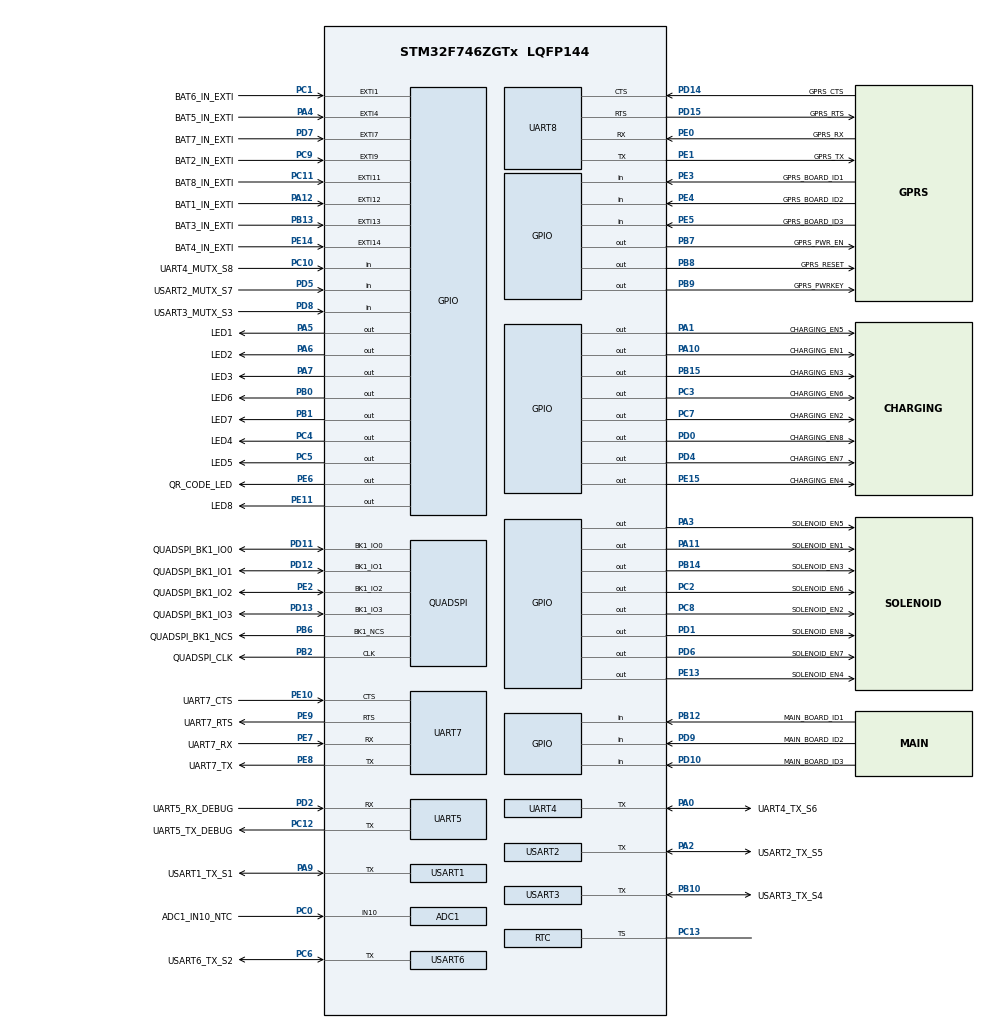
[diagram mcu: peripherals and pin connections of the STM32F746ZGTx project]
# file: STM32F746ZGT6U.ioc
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ADC1.Channel-1\#ChannelRegularConversion=ADC_CHANNEL_10
ADC1.Channel-2\#ChannelRegularConversion=ADC_CHANNEL_TEMPSENSOR
ADC1.ClockPrescaler=ADC_CLOCK_SYNC_PCLK_DIV8
ADC1.DiscontinuousConvMode=ENABLE
ADC1.NbrOfConversion=2
ADC1.NbrOfConversionFlag=1
ADC1.NbrOfDiscConversion=2
ADC1.Rank-1\#ChannelRegularConversion=1
ADC1.Rank-2\#ChannelRegularConversion=2
ADC1.SamplingTime-1\#ChannelRegularConversion=ADC_SAMPLETIME_480CYCLES
ADC1.SamplingTime-2\#ChannelRegularConversion=ADC_SAMPLETIME_480CYCLES
ADC1.ScanConvMode=ENABLE
ADC1.master=1
FREERTOS.Tasks01=defaultTask,0,128,StartDefaultTask,Default,NULL
Mcu.Family=STM32F7
Mcu.Name=STM32F746ZGTx
Mcu.Package=LQFP144
NVIC.EXTI15_10_IRQn=true\:5\:0\:false\:true\:true\:8\:true\:true\:true
NVIC.EXTI1_IRQn=true\:5\:0\:false\:true\:true\:2\:true\:true\:true
NVIC.EXTI4_IRQn=true\:5\:0\:false\:true\:true\:3\:true\:true\:true
NVIC.EXTI9_5_IRQn=true\:5\:0\:false\:true\:true\:4\:true\:true\:true
NVIC.PriorityGroup=NVIC_PRIORITYGROUP_4
NVIC.TIM6_DAC_IRQn=true\:5\:0\:false\:true\:true\:11\:true\:true\:true
NVIC.UART4_IRQn=true\:5\:0\:false\:true\:true\:9\:true\:true\:true
NVIC.UART5_IRQn=true\:5\:0\:false\:true\:true\:10\:true\:true\:true
NVIC.UART7_IRQn=true\:5\:0\:false\:true\:true\:13\:true\:true\:true
NVIC.UART8_IRQn=true\:5\:0\:false\:true\:true\:14\:true\:true\:true
NVIC.USART1_IRQn=true\:5\:0\:false\:true\:true\:5\:true\:true\:true
NVIC.USART2_IRQn=true\:5\:0\:false\:true\:true\:6\:true\:true\:true
NVIC.USART3_IRQn=true\:5\:0\:false\:true\:true\:7\:true\:true\:true
NVIC.USART6_IRQn=true\:5\:0\:false\:true\:true\:12\:true\:true\:true
NVIC.WWDG_IRQn=true\:5\:0\:false\:true\:true\:1\:true\:true\:true
PA0/WKUP.GPIO_Label=UART4_TX_S6
PA0/WKUP.GPIO_Speed=GPIO_SPEED_FREQ_HIGH
PA0/WKUP.Mode=Half_duplex(single_wire_mode)
PA0/WKUP.Signal=UART4_TX
PA1.GPIO_Label=CHARGING_EN5
PA1.GPIO_PuPd=GPIO_PULLDOWN
PA1.Signal=GPIO_Output
PA10.GPIO_Label=CHARGING_EN1
PA10.GPIO_PuPd=GPIO_PULLDOWN
PA10.Signal=GPIO_Output
PA11.GPIO_Label=SOLENOID_EN1
PA11.GPIO_PuPd=GPIO_PULLDOWN
PA11.Signal=GPIO_Output
PA12.GPIO_Label=BAT1_IN_EXTI
PA12.GPIO_ModeDefaultEXTI=GPIO_MODE_IT_RISING_FALLING
PA12.Signal=GPXTI12
PA13.GPIO_Label=JTMS_SWDIO
PA13.Mode=JTAG_5_pins
PA13.Signal=SYS_JTMS-SWDIO
PA14.GPIO_Label=JTCK_SWCLK
PA14.Mode=JTAG_5_pins
PA14.Signal=SYS_JTCK-SWCLK
PA15.GPIO_Label=JTDI
PA15.Mode=JTAG_5_pins
PA15.Signal=SYS_JTDI
PA2.GPIO_Label=USART2_TX_S5
PA2.GPIO_Speed=GPIO_SPEED_FREQ_HIGH
PA2.Mode=Half_duplex(single_wire_mode)
PA2.Signal=USART2_TX
PA3.GPIO_Label=SOLENOID_EN5
PA3.GPIO_PuPd=GPIO_PULLDOWN
PA3.Signal=GPIO_Output
PA4.GPIO_Label=BAT5_IN_EXTI
PA4.GPIO_ModeDefaultEXTI=GPIO_MODE_IT_RISING_FALLING
PA4.Signal=GPXTI4
PA5.GPIO_Label=LED1
PA5.GPIO_PuPd=GPIO_PULLDOWN
PA5.Signal=GPIO_Output
PA6.GPIO_Label=LED2
PA6.GPIO_PuPd=GPIO_PULLDOWN
PA6.Signal=GPIO_Output
PA7.GPIO_Label=LED3
PA7.GPIO_PuPd=GPIO_PULLDOWN
PA7.Signal=GPIO_Output
PA9.GPIO_Label=USART1_TX_S1
PA9.GPIO_Speed=GPIO_SPEED_FREQ_HIGH
PA9.Mode=Half_duplex(single_wire_mode)
PA9.Signal=USART1_TX
PB0.GPIO_Label=LED6
PB0.GPIO_PuPd=GPIO_PULLDOWN
PB0.Signal=GPIO_Output
PB1.GPIO_Label=LED7
PB1.GPIO_PuPd=GPIO_PULLDOWN
PB1.Signal=GPIO_Output
PB10.GPIO_Label=USART3_TX_S4
PB10.GPIO_Speed=GPIO_SPEED_FREQ_HIGH
PB10.Mode=Half_duplex(single_wire_mode)
PB10.Signal=USART3_TX
PB12.GPIO_Label=MAIN_BOARD_ID1
PB12.Signal=GPIO_Input
PB13.GPIO_Label=BAT3_IN_EXTI
PB13.GPIO_ModeDefaultEXTI=GPIO_MODE_IT_RISING_FALLING
PB13.Signal=GPXTI13
PB14.GPIO_Label=SOLENOID_EN3
PB14.GPIO_PuPd=GPIO_PULLDOWN
PB14.Signal=GPIO_Output
PB15.GPIO_Label=CHARGING_EN3
PB15.GPIO_PuPd=GPIO_PULLDOWN
PB15.Signal=GPIO_Output
PB2.GPIO_Label=QUADSPI_CLK
PB2.Mode=Single Bank 1
PB2.Signal=QUADSPI_CLK
PB3.GPIO_Label=JTDO_SWO
PB3.Mode=JTAG_5_pins
PB3.Signal=SYS_JTDO-SWO
PB4.GPIO_Label=JTRST
PB4.Mode=JTAG_5_pins
PB4.Signal=SYS_JTRST
PB6.GPIO_Label=QUADSPI_BK1_NCS
PB6.Mode=Single Bank 1
PB6.Signal=QUADSPI_BK1_NCS
PB7.GPIO_Label=GPRS_PWR_EN
PB7.GPIO_PuPd=GPIO_PULLDOWN
PB7.Signal=GPIO_Output
PB8.GPIO_Label=GPRS_RESET
PB8.GPIO_PuPd=GPIO_PULLDOWN
PB8.Signal=GPIO_Output
PB9.GPIO_Label=GPRS_PWRKEY
PB9.GPIO_PuPd=GPIO_PULLDOWN
PB9.Signal=GPIO_Output
PC0.GPIO_Label=ADC1_IN10_NTC
PC0.Signal=ADCx_IN10
PC1.GPIO_Label=BAT6_IN_EXTI
PC1.GPIO_ModeDefaultEXTI=GPIO_MODE_IT_RISING_FALLING
PC1.Signal=GPXTI1
PC10.GPIO_Label=UART4_MUTX_S8
PC10.Signal=GPIO_Input
PC11.GPIO_Label=BAT8_IN_EXTI
PC11.GPIO_ModeDefaultEXTI=GPIO_MODE_IT_RISING_FALLING
PC11.Signal=GPXTI11
PC12.GPIO_Label=UART5_TX_DEBUG
PC12.GPIO_Speed=GPIO_SPEED_FREQ_HIGH
PC12.Mode=Asynchronous
PC12.Signal=UART5_TX
PC13.Mode=Timestamp enabled - Input Enabled to TS
PC13.Signal=RTC_TS
PC14/OSC32_IN.GPIO_Label=RCC_OSC32_IN
PC14/OSC32_IN.Mode=LSE-External-Oscillator
PC14/OSC32_IN.Signal=RCC_OSC32_IN
PC15/OSC32_OUT.GPIO_Label=RCC_OSC32_OUT
PC15/OSC32_OUT.Mode=LSE-External-Oscillator
PC15/OSC32_OUT.Signal=RCC_OSC32_OUT
PC2.GPIO_Label=SOLENOID_EN6
PC2.GPIO_PuPd=GPIO_PULLDOWN
PC2.Signal=GPIO_Output
PC3.GPIO_Label=CHARGING_EN6
PC3.GPIO_PuPd=GPIO_PULLDOWN
PC3.Signal=GPIO_Output
PC4.GPIO_Label=LED4
PC4.GPIO_PuPd=GPIO_PULLDOWN
PC4.Signal=GPIO_Output
PC5.GPIO_Label=LED5
PC5.GPIO_PuPd=GPIO_PULLDOWN
PC5.Signal=GPIO_Output
PC6.GPIO_Label=USART6_TX_S2
PC6.GPIO_Speed=GPIO_SPEED_FREQ_HIGH
PC6.Mode=Half_duplex(single_wire_mode)
PC6.Signal=USART6_TX
PC7.GPIO_Label=CHARGING_EN2
PC7.GPIO_PuPd=GPIO_PULLDOWN
PC7.Signal=GPIO_Output
PC8.GPIO_Label=SOLENOID_EN2
PC8.GPIO_PuPd=GPIO_PULLDOWN
PC8.Signal=GPIO_Output
PC9.GPIO_Label=BAT2_IN_EXTI
PC9.GPIO_ModeDefaultEXTI=GPIO_MODE_IT_RISING_FALLING
PC9.Signal=GPXTI9
PD0.GPIO_Label=CHARGING_EN8
PD0.GPIO_PuPd=GPIO_PULLDOWN
PD0.Signal=GPIO_Output
PD1.GPIO_Label=SOLENOID_EN8
PD1.GPIO_PuPd=GPIO_PULLDOWN
PD1.Signal=GPIO_Output
PD10.GPIO_Label=MAIN_BOARD_ID3
PD10.Signal=GPIO_Input
PD11.GPIO_Label=QUADSPI_BK1_IO0
PD11.Mode=Single Bank 1
PD11.Signal=QUADSPI_BK1_IO0
PD12.GPIO_Label=QUADSPI_BK1_IO1
PD12.Mode=Single Bank 1
PD12.Signal=QUADSPI_BK1_IO1
PD13.GPIO_Label=QUADSPI_BK1_IO3
PD13.Mode=Single Bank 1
PD13.Signal=QUADSPI_BK1_IO3
PD14.GPIO_Label=GPRS_CTS
PD14.GPIO_Speed=GPIO_SPEED_FREQ_MEDIUM
PD14.Mode=CTS_RTS
PD14.Signal=UART8_CTS
PD15.GPIO_Label=GPRS_RTS
PD15.GPIO_Speed=GPIO_SPEED_FREQ_MEDIUM
PD15.Mode=CTS_RTS
PD15.Signal=UART8_RTS
PD2.GPIO_Label=UART5_RX_DEBUG
PD2.GPIO_Speed=GPIO_SPEED_FREQ_HIGH
PD2.Mode=Asynchronous
PD2.Signal=UART5_RX
PD4.GPIO_Label=CHARGING_EN7
PD4.GPIO_PuPd=GPIO_PULLDOWN
PD4.Signal=GPIO_Output
PD5.GPIO_Label=USART2_MUTX_S7
PD5.Signal=GPIO_Input
PD6.GPIO_Label=SOLENOID_EN7
PD6.GPIO_PuPd=GPIO_PULLDOWN
PD6.Signal=GPIO_Output
PD7.GPIO_Label=BAT7_IN_EXTI
PD7.GPIO_ModeDefaultEXTI=GPIO_MODE_IT_RISING_FALLING
PD7.Signal=GPXTI7
PD8.GPIO_Label=USART3_MUTX_S3
PD8.Signal=GPIO_Input
PD9.GPIO_Label=MAIN_BOARD_ID2
PD9.Signal=GPIO_Input
PE0.GPIO_Label=GPRS_RX
PE0.GPIO_Speed=GPIO_SPEED_FREQ_HIGH
PE0.Mode=Asynchronous
PE0.Signal=UART8_RX
PE1.GPIO_Label=GPRS_TX
PE1.GPIO_Speed=GPIO_SPEED_FREQ_HIGH
PE1.Mode=Asynchronous
PE1.Signal=UART8_TX
PE10.GPIO_Label=UART7_CTS
PE10.GPIO_Speed=GPIO_SPEED_FREQ_MEDIUM
PE10.Mode=CTS_RTS
PE10.Signal=UART7_CTS
PE11.GPIO_Label=LED8
PE11.GPIO_PuPd=GPIO_PULLDOWN
PE11.Signal=GPIO_Output
PE13.GPIO_Label=SOLENOID_EN4
PE13.GPIO_PuPd=GPIO_PULLDOWN
PE13.Signal=GPIO_Output
PE14.GPIO_Label=BAT4_IN_EXTI
PE14.GPIO_ModeDefaultEXTI=GPIO_MODE_IT_RISING_FALLING
PE14.Signal=GPXTI14
PE15.GPIO_Label=CHARGING_EN4
PE15.GPIO_PuPd=GPIO_PULLDOWN
PE15.Signal=GPIO_Output
PE2.GPIO_Label=QUADSPI_BK1_IO2
PE2.Mode=Single Bank 1
PE2.Signal=QUADSPI_BK1_IO2
PE3.GPIO_Label=GPRS_BOARD_ID1
PE3.Signal=GPIO_Input
PE4.GPIO_Label=GPRS_BOARD_ID2
PE4.Signal=GPIO_Input
PE5.GPIO_Label=GPRS_BOARD_ID3
PE5.Signal=GPIO_Input
PE6.GPIO_Label=QR_CODE_LED
PE6.GPIO_PuPd=GPIO_PULLDOWN
PE6.Signal=GPIO_Output
PE7.GPIO_Label=UART7_RX
PE7.GPIO_Speed=GPIO_SPEED_FREQ_HIGH
PE7.Mode=Asynchronous
PE7.Signal=UART7_RX
PE8.GPIO_Label=UART7_TX
PE8.GPIO_Speed=GPIO_SPEED_FREQ_HIGH
PE8.Mode=Asynchronous
PE8.Signal=UART7_TX
PE9.GPIO_Label=UART7_RTS
PE9.GPIO_Speed=GPIO_SPEED_FREQ_MEDIUM
PE9.Mode=CTS_RTS
PE9.Signal=UART7_RTS
PH0/OSC_IN.GPIO_Label=RCC_OSC_IN
PH0/OSC_IN.Mode=HSE-External-Oscillator
PH0/OSC_IN.Signal=RCC_OSC_IN
PH1/OSC_OUT.GPIO_Label=RCC_OSC_OUT
PH1/OSC_OUT.Mode=HSE-External-Oscillator
PH1/OSC_OUT.Signal=RCC_OSC_OUT
ProjectManager.HeapSize=0x200
ProjectManager.StackSize=0x400
ProjectManager.TargetToolchain=Makefile
QUADSPI.ChipSelectHighTime=QSPI_CS_HIGH_TIME_2_CYCLE
QUADSPI.ClockPrescaler=1
QUADSPI.FifoThreshold=4
QUADSPI.FlashSize=26
QUADSPI.SampleShifting=QSPI_SAMPLE_SHIFTING_HALFCYCLE
RCC.AHBFreq_Value=208000000
RCC.APB1CLKDivider=RCC_HCLK_DIV4
RCC.APB1Freq_Value=52000000
RCC.APB1TimFreq_Value=104000000
RCC.APB2CLKDivider=RCC_HCLK_DIV2
RCC.APB2Freq_Value=104000000
RCC.APB2TimFreq_Value=208000000
RCC.CortexFreq_Value=208000000
RCC.HCLKFreq_Value=208000000
RCC.HSE_VALUE=25000000
RCC.HSI_VALUE=16000000
RCC.PLLM=25
RCC.PLLN=416
RCC.PLLQ=9
RCC.PLLSourceVirtual=RCC_PLLSOURCE_HSE
RCC.RTCClockSelection=RCC_RTCCLKSOURCE_LSE
RCC.SYSCLKFreq_VALUE=208000000
RCC.SYSCLKSource=RCC_SYSCLKSOURCE_PLLCLK
RCC.USBFreq_Value=46222222.222222224
RCC.VCOOutputFreq_Value=416000000
SH.ADCx_IN10.0=ADC1_IN10,IN10
TIM6.Period=999
TIM6.Prescaler=51
USART1.VirtualMode-Half_duplex(single_wire_mode)=VM_ASYNC
USART2.VirtualMode-Half_duplex(single_wire_mode)=VM_ASYNC
USART3.VirtualMode-Half_duplex(single_wire_mode)=VM_ASYNC
USART6.VirtualMode-Half_duplex(single_wire_mode)=VM_ASYNC
VP_ADC1_TempSens_Input.Mode=IN-TempSens
VP_CRC_VS_CRC.Mode=CRC_Activate
VP_FATFS_VS_Generic.Mode=User_defined
VP_FREERTOS_VS_CMSIS_V1.Mode=CMSIS_V1
VP_IWDG_VS_IWDG.Mode=IWDG_Activate
VP_RNG_VS_RNG.Mode=RNG_Activate
VP_RTC_VS_RTC_Activate.Mode=RTC_Enabled
VP_RTC_VS_RTC_Calendar.Mode=RTC_Calendar
VP_TIM6_VS_ClockSourceINT.Mode=Enable_Timer
VP_WWDG_VS_WWDG.Mode=WWDG_Activate
board=custom

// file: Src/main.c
/* USER CODE BEGIN Header */

/**
 ******************************************************************************
 * @file           : main.c
 * @brief          : Main program body
 ******************************************************************************
 * @attention
 *
 * <h2><center>&copy; Copyright (c) 2019 STMicroelectronics.
 * All rights reserved.</center></h2>
 *
 * This software component is licensed by ST under Ultimate Liberty license
 * SLA0044, the "License"; You may not use this file except in compliance with
 * the License. You may obtain a copy of the License at:
 *                             www.st.com/SLA0044
 *
 ******************************************************************************
 */
/* USER CODE END Header */

#include "main.h"
#include "cmsis_os.h"
#include "adc.h"
#include "crc.h"
#include "fatfs.h"
#include "iwdg.h"
#include "quadspi.h"
#include "rng.h"
#include "rtc.h"
#include "tim.h"
#include "usart.h"
#include "wwdg.h"
#include "gpio.h"
#include "uart_comm.h"
#ifdef TEST
#include "fml_slot_manage.h"
#endif

#ifdef STM32F730xx
#include "aes.h"
#endif

/* USER CODE BEGIN Includes */
#include "apl_log.h"
#include "apl_exti_chk.h"
/* USER CODE END Includes */

void SystemClock_Config(void);
void MX_FREERTOS_Init(void);
static void MX_NVIC_Init(void);

int main(void)
{

	/* MCU Configuration--------------------------------------------------------*/

	/* Reset of all peripherals, Initializes the Flash interface and the Systick. */
	HAL_Init();

	/* Configure the system clock */
	SystemClock_Config();

	/* Initialize all configured peripherals */

	MX_UART5_Init();
	MX_GPIO_Init();

#if 0

	MX_ADC1_Init();
	MX_QUADSPI_Init();
	MX_UART4_Init();
	MX_UART5_Init();
	MX_UART7_Init();
	MX_UART8_Init();
	MX_USART1_UART_Init();
	MX_USART2_UART_Init();
	MX_USART3_UART_Init();
	MX_USART6_UART_Init();
	MX_RTC_Init();
	//	MX_WWDG_Init();
	//	MX_IWDG_Init();
	MX_TIM6_Init();
	MX_RNG_Init();
	MX_CRC_Init();

	#ifdef STM32F730xx
	MX_AES_Init();
	#endif
#endif
	/* Initialize interrupts */
	MX_NVIC_Init();
	/* USER CODE BEGIN 2 */
	//create_bat_in_check_task();
	/* USER CODE END 2 */

	/* Call init function for freertos objects (in freertos.c) */
#if 0
	log_module_test();
	fml_slot_test();
    // gprs_module_test();
#else
	MX_FREERTOS_Init();
#endif
 	start_uart_service();
	/* Start scheduler */
	osKernelStart();

	/* We should never get here as control is now taken by the scheduler */

	/* Infinite loop */
	while (1) {

	}
}	/* main */

void SystemClock_Config(void)
{
	RCC_OscInitTypeDef RCC_OscInitStruct         = { 0 };
	RCC_ClkInitTypeDef RCC_ClkInitStruct         = { 0 };
	RCC_PeriphCLKInitTypeDef PeriphClkInitStruct = { 0 };

	/** Configure LSE Drive Capability
	 */
	HAL_PWR_EnableBkUpAccess();
	__HAL_RCC_LSEDRIVE_CONFIG(RCC_LSEDRIVE_LOW);

	/** Configure the main internal regulator output voltage
	 */
	__HAL_RCC_PWR_CLK_ENABLE();
	__HAL_PWR_VOLTAGESCALING_CONFIG(PWR_REGULATOR_VOLTAGE_SCALE1);

	/** Initializes the CPU, AHB and APB busses clocks
	 */
	#ifdef STM32F730xx
	RCC_OscInitStruct.OscillatorType = RCC_OSCILLATORTYPE_LSI | RCC_OSCILLATORTYPE_HSE
	  | RCC_OSCILLATORTYPE_LSE;
	RCC_OscInitStruct.HSEState      = RCC_HSE_ON;
	RCC_OscInitStruct.LSEState      = RCC_LSE_ON;
	RCC_OscInitStruct.LSIState      = RCC_LSI_ON;
	RCC_OscInitStruct.PLL.PLLState  = RCC_PLL_ON;
	RCC_OscInitStruct.PLL.PLLSource = RCC_PLLSOURCE_HSE;
	RCC_OscInitStruct.PLL.PLLM = 12;
	RCC_OscInitStruct.PLL.PLLN = 208;
	#elif defined(STM32F746xx)
	RCC_OscInitStruct.OscillatorType = RCC_OSCILLATORTYPE_HSI | RCC_OSCILLATORTYPE_LSI
	  | RCC_OSCILLATORTYPE_LSE;
	RCC_OscInitStruct.LSEState = RCC_LSE_ON;
	RCC_OscInitStruct.HSIState = RCC_HSI_ON;
	RCC_OscInitStruct.HSICalibrationValue = RCC_HSICALIBRATION_DEFAULT;
	RCC_OscInitStruct.LSIState		= RCC_LSI_ON;
	RCC_OscInitStruct.PLL.PLLState	= RCC_PLL_ON;
	RCC_OscInitStruct.PLL.PLLSource = RCC_PLLSOURCE_HSI;
	RCC_OscInitStruct.PLL.PLLM		= 8;
	RCC_OscInitStruct.PLL.PLLN		= 208;
	#endif

	RCC_OscInitStruct.PLL.PLLP = RCC_PLLP_DIV2;
	RCC_OscInitStruct.PLL.PLLQ = 9;
	if (HAL_RCC_OscConfig(&RCC_OscInitStruct) != HAL_OK) {
		Error_Handler();
	}

	/** Activate the Over-Drive mode
	 */
	if (HAL_PWREx_EnableOverDrive() != HAL_OK) {
		Error_Handler();
	}

	/** Initializes the CPU, AHB and APB busses clocks
	 */
	RCC_ClkInitStruct.ClockType = RCC_CLOCKTYPE_HCLK | RCC_CLOCKTYPE_SYSCLK
	  | RCC_CLOCKTYPE_PCLK1 | RCC_CLOCKTYPE_PCLK2;
	RCC_ClkInitStruct.SYSCLKSource   = RCC_SYSCLKSOURCE_PLLCLK;
	RCC_ClkInitStruct.AHBCLKDivider  = RCC_SYSCLK_DIV1;
	RCC_ClkInitStruct.APB1CLKDivider = RCC_HCLK_DIV4;
	RCC_ClkInitStruct.APB2CLKDivider = RCC_HCLK_DIV2;

	if (HAL_RCC_ClockConfig(&RCC_ClkInitStruct, FLASH_LATENCY_6) != HAL_OK) {
		Error_Handler();
	}
	PeriphClkInitStruct.PeriphClockSelection = RCC_PERIPHCLK_RTC | RCC_PERIPHCLK_USART1
	  | RCC_PERIPHCLK_USART2 | RCC_PERIPHCLK_USART3
	  | RCC_PERIPHCLK_USART6 | RCC_PERIPHCLK_UART4
	  | RCC_PERIPHCLK_UART5 | RCC_PERIPHCLK_UART7
	  | RCC_PERIPHCLK_UART8 | RCC_PERIPHCLK_CLK48;
	PeriphClkInitStruct.RTCClockSelection    = RCC_RTCCLKSOURCE_LSE;
	PeriphClkInitStruct.Usart1ClockSelection = RCC_USART1CLKSOURCE_PCLK2;
	PeriphClkInitStruct.Usart2ClockSelection = RCC_USART2CLKSOURCE_PCLK1;
	PeriphClkInitStruct.Usart3ClockSelection = RCC_USART3CLKSOURCE_PCLK1;
	PeriphClkInitStruct.Uart4ClockSelection  = RCC_UART4CLKSOURCE_PCLK1;
	PeriphClkInitStruct.Uart5ClockSelection  = RCC_UART5CLKSOURCE_PCLK1;
	PeriphClkInitStruct.Usart6ClockSelection = RCC_USART6CLKSOURCE_PCLK2;
	PeriphClkInitStruct.Uart7ClockSelection  = RCC_UART7CLKSOURCE_PCLK1;
	PeriphClkInitStruct.Uart8ClockSelection  = RCC_UART8CLKSOURCE_PCLK1;
	PeriphClkInitStruct.Clk48ClockSelection  = RCC_CLK48SOURCE_PLL;
	if (HAL_RCCEx_PeriphCLKConfig(&PeriphClkInitStruct) != HAL_OK) {
		Error_Handler();
	}
}	/* SystemClock_Config */

/**
 * @brief NVIC Configuration.
 * @retval None
 */
static void MX_NVIC_Init(void)
{
	/* EXTI1_IRQn interrupt configuration */
	HAL_NVIC_SetPriority(EXTI1_IRQn, 5, 0);
	HAL_NVIC_EnableIRQ(EXTI1_IRQn);
	/* EXTI4_IRQn interrupt configuration */
	HAL_NVIC_SetPriority(EXTI4_IRQn, 5, 0);
	HAL_NVIC_EnableIRQ(EXTI4_IRQn);
	/* EXTI9_5_IRQn interrupt configuration */
	HAL_NVIC_SetPriority(EXTI9_5_IRQn, 5, 0);
	HAL_NVIC_EnableIRQ(EXTI9_5_IRQn);
	/* USART1_IRQn interrupt configuration */
	HAL_NVIC_SetPriority(USART1_IRQn, 5, 0);
	HAL_NVIC_EnableIRQ(USART1_IRQn);
	/* USART2_IRQn interrupt configuration */
	HAL_NVIC_SetPriority(USART2_IRQn, 5, 0);
	HAL_NVIC_EnableIRQ(USART2_IRQn);
	/* USART3_IRQn interrupt configuration */
	HAL_NVIC_SetPriority(USART3_IRQn, 5, 0);
	HAL_NVIC_EnableIRQ(USART3_IRQn);
	/* EXTI15_10_IRQn interrupt configuration */
	HAL_NVIC_SetPriority(EXTI15_10_IRQn, 5, 0);
	HAL_NVIC_EnableIRQ(EXTI15_10_IRQn);
	/* UART4_IRQn interrupt configuration */
	HAL_NVIC_SetPriority(UART4_IRQn, 5, 0);
	HAL_NVIC_EnableIRQ(UART4_IRQn);
	/* UART5_IRQn interrupt configuration */
	HAL_NVIC_SetPriority(UART5_IRQn, 5, 0);
	HAL_NVIC_EnableIRQ(UART5_IRQn);
	/* USART6_IRQn interrupt configuration */
	HAL_NVIC_SetPriority(USART6_IRQn, 5, 0);
	HAL_NVIC_EnableIRQ(USART6_IRQn);
	/* UART7_IRQn interrupt configuration */
	HAL_NVIC_SetPriority(UART7_IRQn, 5, 0);
	HAL_NVIC_EnableIRQ(UART7_IRQn);
	/* UART8_IRQn interrupt configuration */
	HAL_NVIC_SetPriority(UART8_IRQn, 5, 0);
	HAL_NVIC_EnableIRQ(UART8_IRQn);
	/* WWDG_IRQn interrupt configuration */
	HAL_NVIC_SetPriority(WWDG_IRQn, 5, 0);
	HAL_NVIC_EnableIRQ(WWDG_IRQn);
	/* TIM6_DAC_IRQn interrupt configuration */
	HAL_NVIC_SetPriority(TIM6_DAC_IRQn, 5, 0);
	HAL_NVIC_EnableIRQ(TIM6_DAC_IRQn);
}	/* MX_NVIC_Init */
void HAL_TIM_PeriodElapsedCallback(TIM_HandleTypeDef *htim)
{
  if (htim->Instance == TIM7) {
    HAL_IncTick();
  }
}

void Error_Handler(void)
{
}

#ifdef  USE_FULL_ASSERT

/**
 * @brief  Reports the name of the source file and the source line number
 *         where the assert_param error has occurred.
 * @param  file: pointer to the source file name
 * @param  line: assert_param error line source number
 * @retval None
 */
void assert_failed(uint8_t *file, uint32_t line)
{
	/* USER CODE BEGIN 6 */

	/* User can add his own implementation to report the file name and line number,
	 * tex: printf("Wrong parameters value: file %s on line %d\r\n", file, line) */
	/* USER CODE END 6 */
}

#endif	/* USE_FULL_ASSERT */

/************************ (C) COPYRIGHT STMicroelectronics *****END OF FILE****/

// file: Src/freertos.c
/* USER CODE BEGIN Header */

/**
 ******************************************************************************
 * File Name          : freertos.c
 * Description        : Code for freertos applications
 ******************************************************************************
 * @attention
 *
 * <h2><center>&copy; Copyright (c) 2019 STMicroelectronics.
 * All rights reserved.</center></h2>
 *
 * This software component is licensed by ST under Ultimate Liberty license
 * SLA0044, the "License"; You may not use this file except in compliance with
 * the License. You may obtain a copy of the License at:
 *                             www.st.com/SLA0044
 *
 ******************************************************************************
 */
/* USER CODE END Header */

#include "FreeRTOS.h"
#include "task.h"
#include "main.h"
#include "cmsis_os.h"
#include "stdio.h"
#include "test_battery.h"

osThreadId defaultTaskHandle;

void StartDefaultTask(void const *argument);

extern void MX_FATFS_Init(void);
void MX_FREERTOS_Init(void);/* (MISRA C 2004 rule 8.1) */

void MX_FREERTOS_Init(void)
{

	/* Create the thread(s) */
	/* definition and creation of defaultTask */
	osThreadDef(defaultTask, StartDefaultTask, osPriorityNormal, 0, 1024);
	defaultTaskHandle = osThreadCreate(osThread(defaultTask), NULL);

}

void StartDefaultTask(void const *argument)
{
	/* init code for FATFS */
	//MX_FATFS_Init();

	/* USER CODE BEGIN StartDefaultTask */
	/* Infinite loop */
	//osDelay(2000);
	//test_bat_protoc();
		printf("aaaaa\r\n");
	for (;;) {
		HAL_Delay(1000);
		HAL_GPIO_WritePin(GPIOB, LED6_Pin, GPIO_PIN_SET);
		HAL_Delay(1000);
		HAL_GPIO_WritePin(GPIOB, LED6_Pin, GPIO_PIN_RESET);

		//test_bat_protoc();
		printf("uuuuuuuu\r\n");
	}
	/* USER CODE END StartDefaultTask */
}

/************************ (C) COPYRIGHT STMicroelectronics *****END OF FILE****/
